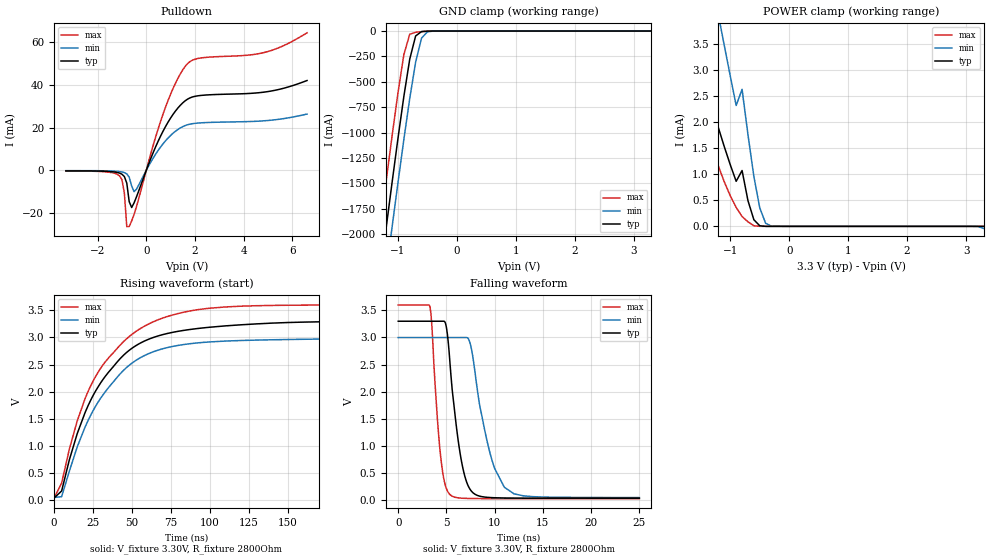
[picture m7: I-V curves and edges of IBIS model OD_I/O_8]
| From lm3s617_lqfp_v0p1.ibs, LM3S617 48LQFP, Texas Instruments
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[Model]   OD_I/O_8
Model_type   I/O_open_drain
Polarity   Inverting
Vinl = 1.26
Vinh = 2.04
Vmeas = 1.65
Rref = 2800
Vref = 3.3
| variable   typ   min   max
C_comp   9.739pF   9.739pF   9.739pF
[Model Spec]
Vinh+   1.91   1.78   2.04
Vinh-   1.90   1.76   2.03
Vinl+   1.40   1.27   1.54
Vinl-   1.39   1.26   1.53
| variable   typ   min   max
[Temperature Range]  25   85   -40
[Voltage Range]   3.3V   3.0V   3.6V
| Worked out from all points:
|   slope of the pulldown table from 0 to 0.495 V, typ, clamps not added: 35.8 ohm
|   GND clamp passes 1 mA (typ) near -0.48 V on its own axis
|   POWER clamp passes 1 mA (typ) near -0.79 V on its own axis
|   falling waveform, V_fixture 3.30V, R_fixture 2800Ohm: 20-80 % time 1.27ns typ, 1.97ns min, 849ps max; typ from 3.3 V to 0.038 V
|   rising waveform, V_fixture 3.30V, R_fixture 2800Ohm: 20-80 % time 34.3ns typ, 34ns min, 35ns max; typ from 0.038 V to 3.3 V
[Pulldown]
|  Voltage   I(typ)   I(min)   I(max)
-3.3V     -256.6uA   -145.6uA   -364.5uA
-1.1V     -1.273mA   -587.5uA   -2.567mA
-900mV    -2.885mA   -1.061mA   -10.54mA
-800mV    -5.993mA   -1.67mA    -26.39mA
-700mV    -14.71mA   -3.215mA   -26.33mA
-600mV    -17.43mA   -7.321mA   -23.73mA
-500mV    -15.26mA   -10mA      -20.66mA
700mV     18.62mA    12.61mA    26.75mA
1.2V      27.84mA    18.36mA    40.91mA
1.7V      33.44mA    21.41mA    50.13mA
4.9V      36.8mA     23.3mA     55.47mA
6.6V      42.15mA    26.42mA    64.53mA
[GND Clamp]
|  Voltage   I(typ)   I(min)   I(max)
-3.3V     -11.72A    -12.12A    -11.3A
-1.4V     -2.845A    -3.285A    -2.387A
-1.3V     -2.39A     -2.831A    -1.93A
-1.2V     -1.938A    -2.38A     -1.478A
-1.1V     -1.494A    -1.934A    -1.036A
-1V       -1.059A    -1.496A    -610.6mA
-900mV    -645mA     -1.069A    -232.9mA
-800mV    -277.1mA   -664.4mA   -31.59mA
-700mV    -48.56mA   -306.6mA   -12.09mA
-600mV    -5.558mA   -70.2mA    -6.272mA
-500mV    -1.167mA   -7.879mA   -2.167mA
3.3V      2.282nA    3.101uA    451.3pA
[POWER Clamp]
|  Voltage   I(typ)   I(min)   I(max)
-3.3V     12.41mA    17.26mA    12.22mA
-1.9V     4.919mA    8.328mA    4.074mA
-1.8V     4.445mA    7.705mA    3.587mA
-1.6V     3.533mA    6.47mA     2.675mA
-1.2V     1.89mA     4.055mA    1.153mA
-1.1V     1.526mA    3.468mA    851.4uA
-900mV    866.3uA    2.324mA    364.9uA
-800mV    1.074mA    2.635mA    188.8uA
-600mV    127.8uA    958.5uA    11.41uA
-500mV    11.24uA    355.9uA    954.7nA
-300mV    9.515nA    3.101uA    1.472nA
3.3V      -104.7pA   -40.34uA   119.2pA
[Ramp]
| variable   typ   min   max
dV/dt_f   1.96/1.27n   1.77/1.97n   2.14/0.85n
dV/dt_r   1.96/34.28n   1.77/33.99n   2.14/35.02n
R_load = 2800Ohm
[Falling Waveform]
V_fixture = 3.30V
V_fixture_min = 3.00V
V_fixture_max = 3.60V
R_fixture = 2800Ohm
|   Time   V(typ)   V(min)   V(max)
0s        3.3V       2.999V     3.6V
3.3ns     3.3V       2.999V     3.565V
4.4ns     3.3V       2.999V     807.8mV
5ns       3.185V     2.999V     213.1mV
5.4ns     2.453V     2.999V     99.88mV
6.6ns     681.4mV    2.999V     38.81mV
7.9ns     118.3mV    2.442V     32.22mV
9.4ns     52.32mV    950.9mV    30.55mV
11ns      42.68mV    240.8mV    30.12mV
25ns      37.9mV     50.26mV    29.43mV
[Rising Waveform]
V_fixture = 3.30V
V_fixture_min = 3.00V
V_fixture_max = 3.60V
R_fixture = 2800Ohm
|   Time   V(typ)   V(min)   V(max)
0s        38.01mV    50.67mV    29.45mV
5ns       171.5mV    67.34mV    316.9mV
10ns      750.6mV    541.5mV    947.9mV
15ns      1.229V     983.7mV    1.463V
26ns      1.975V     1.694V     2.241V
44ns      2.654V     2.374V     2.903V
61ns      2.97V      2.705V     3.251V
83ns      3.129V     2.868V     3.463V
110ns     3.213V     2.933V     3.562V
250ns     3.298V     2.994V     3.599V
